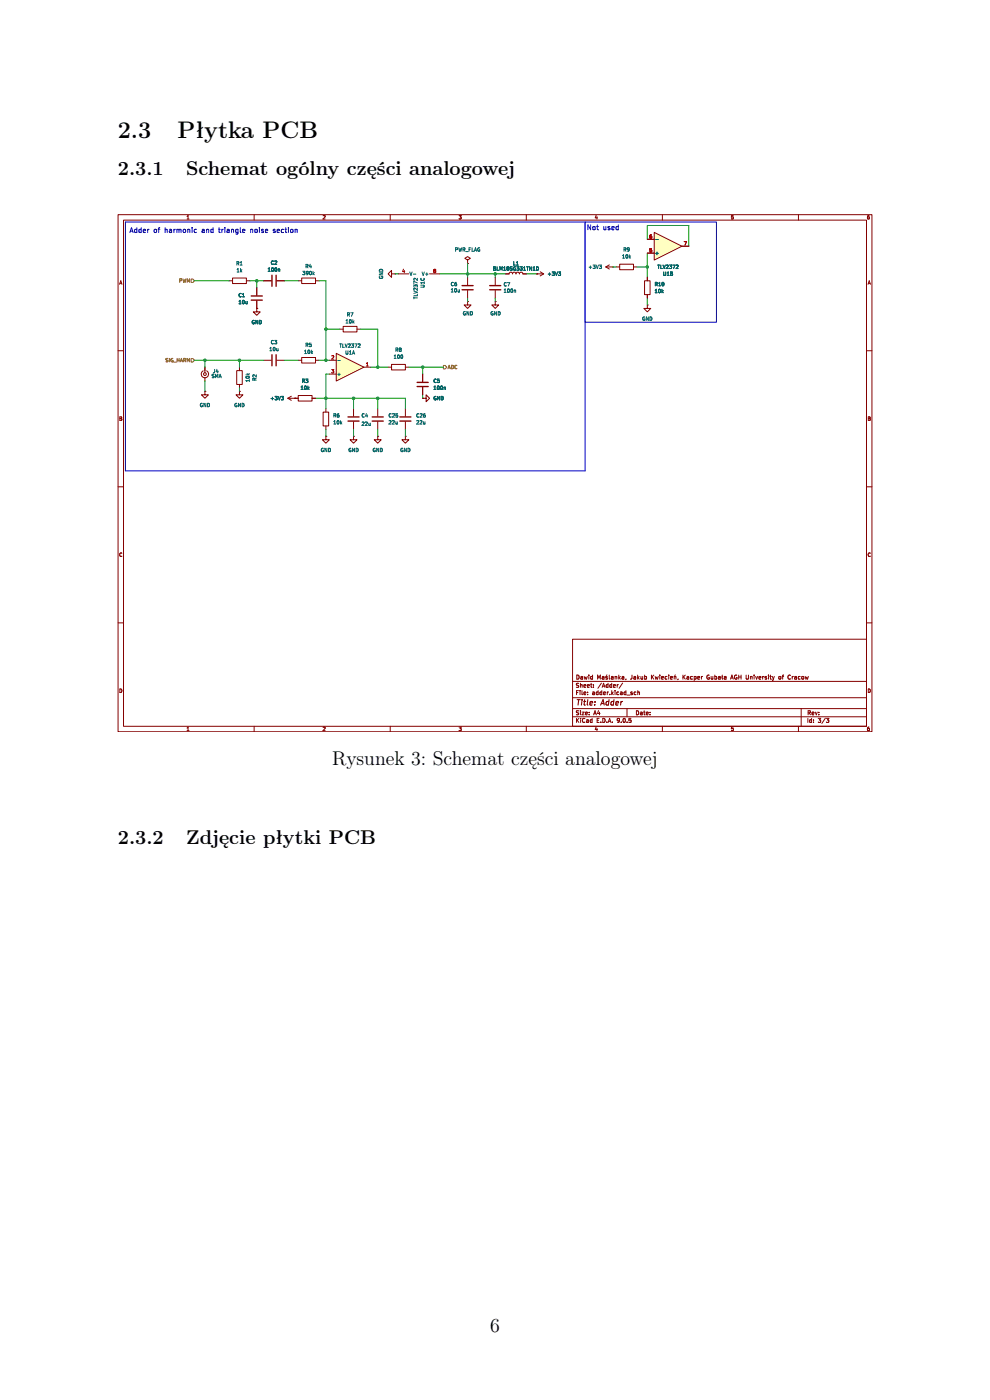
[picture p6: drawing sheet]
<svg xmlns="http://www.w3.org/2000/svg" width="210mm" height="297mm" viewBox="0 0 210 297" stroke-linecap="round" stroke-linejoin="round" font-family="sans-serif">
<defs><g id="words">
<g font-size="5.1">
<text x="25" y="29.2">2.3</text>
<text x="37.7" y="29.2">Płytka PCB</text>
</g>
<g font-size="4.2">
<text x="25" y="37">2.3.1</text>
<text x="39.5" y="37">Schemat ogólny części analogowej</text>
<text x="70.4" y="162.4">Rysunek 3: Schemat części analogowej</text>
<text x="25" y="179">2.3.2</text>
<text x="39.5" y="179">Zdjęcie płytki PCB</text>
<text x="104" y="282.5">6</text>
</g>
<g font-size="4.2" fill="#840000">
<text x="39.5" y="46.5">1</text>
<text x="68.3" y="46.5">2</text>
<text x="97.2" y="46.5">3</text>
<text x="126.1" y="46.5">4</text>
<text x="154.9" y="46.5">5</text>
<text x="183.8" y="46.5">6</text>
<text x="137" y="53.6">5</text>
<text x="48.7" y="57.7">1k 100n390k</text>
<text x="24.1" y="60.4">A</text>
<text x="48.4" y="64.5">10u</text>
<text x="93.4" y="62">10u</text>
<text x="103.9" y="62.1">100n</text>
<text x="182.8" y="60.4">A</text>
<text x="71.1" y="68.6">10k</text>
<text x="24.2" y="89.2">B</text>
<text x="53.6" y="84.9">+3V3</text>
<text x="68.5" y="90">10k22u22u22u</text>
<text x="88.3" y="84.9">GND</text>
<text x="182.9" y="89.2">B</text>
<text x="24.1" y="118.1">C</text>
<text x="182.9" y="118.1">C</text>
<text x="24" y="146.9">D</text>
<text x="122" y="149.6">Title: Adder</text>
<text x="122" y="147.4">File: adder.kicad ch</text>
<text x="122" y="144.1">Dawid Maślanka, Jakub Kwiecień, Kacper Gubała</text>
<text x="182.8" y="146.9">D</text>
<text x="39.5" y="155">1</text>
<text x="68.3" y="155">2</text>
<text x="97.2" y="155">3</text>
<text x="122" y="153.3">KiCad E.D.A. 9.0.5</text>
<text x="122" y="151.7">Size: A4</text>
<text x="126.1" y="155">4</text>
<text x="134.7" y="151.7">Date:</text>
<text x="154.9" y="155">5</text>
<text x="171.1" y="151.7">Rev:</text>
<text x="171.1" y="153.3">Id: 3/3</text>
<text x="183.8" y="155">6</text>
</g>
<g font-size="4.2" fill="#0000c2">
<text x="4.8" y="49.4">Adder of harmonic and triangle noise section</text>
<text x="119.8" y="48.8">Not used</text>
</g>
<g font-size="4.2" fill="#006464">
<text x="88.3" y="53.3">PWR LAG</text>
<text x="130.4" y="53.3">R9</text>
<text x="48.2" y="56.3">R1 C2</text>
<text x="53.9" y="57.6">100nR4</text>
<text x="55.6" y="56.1">C2</text>
<text x="107.1" y="56.3">L1</text>
<text x="112.4" y="58.5">+3V3</text>
<text x="137.7" y="58.5">U1B</text>
<text x="81.2" y="62.8" transform="rotate(-90 81.2 62.8)">GND</text>
<text x="90" y="64.1" transform="rotate(-90 90 64.1)">U1C</text>
<text x="136.7" y="62.1">10k</text>
<text x="49.7" y="68.7">GND</text>
<text x="71.7" y="67.1">R7</text>
<text x="100.4" y="66.9">GND</text>
<text x="132.6" y="68">GND</text>
<text x="55.6" y="73">C3 R5</text>
<text x="70.1" y="75.2">U1A</text>
<text x="71.4" y="76.8">-</text>
<text x="76.9" y="77.7">1</text>
<text x="81.4" y="76.1">100</text>
<text x="62.2" y="81.2">R3</text>
<text x="89.1" y="82.7">100n</text>
<text x="38.7" y="86.3">GND</text>
<text x="46.1" y="86.3">GND</text>
<text x="64.4" y="95.9">GND GND</text>
<text x="70.2" y="95.9">GND GND</text>
</g>
<g font-size="4.2" fill="#009600">
<text x="137" y="50.6">6</text>
<text x="84.7" y="58.5">V+</text>
<text x="121" y="57">+3V3 TLV2372</text>
<text x="48.8" y="63">C1</text>
<text x="93.8" y="60.7">C6</text>
<text x="105" y="60.7">C7</text>
<text x="136.3" y="60.7">R10</text>
<text x="94.5" y="66.9">GND</text>
<text x="54.9" y="74.5">10u 10k</text>
<text x="69.6" y="76.3">2</text>
<text x="41.3" y="80.2">SMA</text>
<text x="43.7" y="79.1">J4</text>
<text x="54.4" y="82.6" transform="rotate(-90 54.4 82.6)">R2</text>
<text x="69.6" y="79.2">3</text>
<text x="90.1" y="81.2">C5</text>
<text x="68.8" y="88.5">R6 C4C25C26</text>
</g>
<g font-size="4.2" fill="#a90000">
<text x="138.9" y="51.1">-</text>
<text x="144.3" y="52.1">7</text>
<text x="84.6" y="58">4V-8</text>
</g>
<g font-size="4.2" fill="#725600">
<text x="29.6" y="59.9">PWM</text>
<text x="29.7" y="76.8">ARM</text>
<text x="94.9" y="78.3">ADC</text>
</g>
<text font-size="2.8" fill="#006464" x="98.4" y="54">F</text>
</g></defs>
<g fill="none" stroke="#840000" stroke-width=".21">
<path d="M25 45.5h160v109.7h-160zM26.2 46.7h157.6v107.4h-157.6zM83.1 58.1v-.7l-.8 .7 .8 .7v-.7h.7M99.2 55.2l.6-.4-.6-.4-.6 .4 .6 .4v.7M99.2 55.9h.1M111.6 45.5v1.2M134.4 56.6h.7M140.5 45.5v1.2M169.4 45.5v1.2M25 74.4h1.2M72.8 69.2h2.9v1.2h-2.9zM82.3 77.9h.8"/>
<path d="M83.1 77.3h2.9v1.2h-2.9zM86 77.9h.7M183.8 74.4h1.2M25 103.3h1.2M183.8 103.3h1.2M25 132.1h1.2M121.5 135.6h62.3v18.5h-62.3zM183.8 132.1h1.2M53.9 154.1v1.1M82.8 154.1v1.1M111.6 154.1v1.1M121.5 152.1h62.3"/>
<path d="M121.5 150.3h62.3M121.5 148h62.3M121.5 144.6h62.3M140.5 154.1v1.1M169.4 154.1v1.1"/>
</g>
<path d="M57.7 58.4v2.3M58.6 58.4v2.3M57.7 75.3v2.3M58.6 75.3v2.3" fill="none" stroke="#840000" stroke-width=".29"/>
<path d="M71.3 75l5.9 2.9-5.9 2.9z" fill="#ffffc2" stroke="#840000" stroke-width=".21"/>
<path d="M64 59h2.9v1.2h-2.9zM64 75.8h2.9v1.2h-2.9zM63.3 83.9h2.9v1.2h-2.9zM66.2 84.5h.7" fill="none" stroke="#840000" stroke-width=".21"/>
<path d="M138.8 49.3l5.8 2.9-5.8 3z" fill="#ffffc2" stroke="#840000" stroke-width=".21"/>
<path d="M26.6 47.1h97.5v52.8h-97.5zM124.1 47.1h27.9v21.3h-27.9z" fill="none" stroke="#0000c2" stroke-width=".21"/>
<g fill="none" stroke="#009600" stroke-width=".21">
<path d="M41.3 59.6h7.3M69.1 59.6v16.8M99.2 55.9v2.2h5.9M137.3 53.7v2.9M137.3 47.8h8.8M43.5 76.4h7.3M69.1 79.4v5.1h-2.2M69.1 69.8h3M76.5 69.8h3.6v8.1M78.7 77.9h3.6M86.7 77.9h3M137.3 63.2v1.5"/>
<path d="M43.5 80.8v2.2M69.1 91.1v1.5M75 91.1v1.5M80.1 91.1v1.5M86 91.1v1.5"/>
</g>
<path d="M66.2 84.5h.7" fill="none" stroke="#840000" stroke-width=".21"/>
<g fill="#009600" stroke="#009600" stroke-width=".21">
<circle cx="80.1" cy="77.9" r=".26"/>
<circle cx="69.1" cy="69.8" r=".26"/>
<circle cx="50.8" cy="76.4" r=".26"/>
</g>
<use href="#words"/>
</svg>
